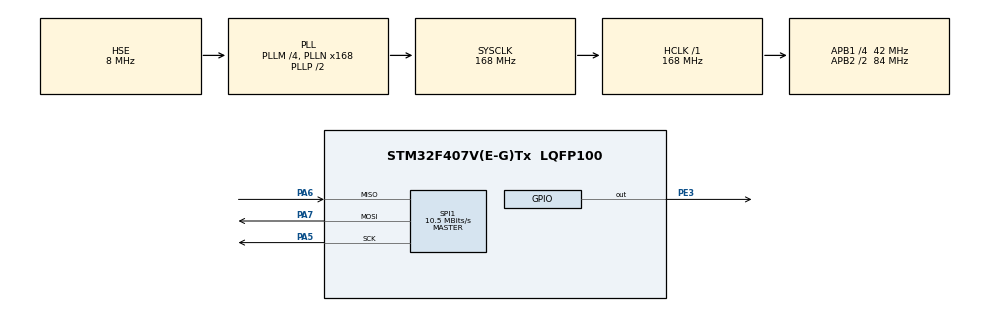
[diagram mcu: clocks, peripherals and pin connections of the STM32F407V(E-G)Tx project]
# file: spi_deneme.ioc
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Mcu.Family=STM32F4
RCC.PLLSourceVirtual=RCC_PLLSOURCE_HSE
PA6.Mode=Full_Duplex_Master
PH0-OSC_IN.Signal=RCC_OSC_IN
RCC.CortexFreq_Value=168000000
PA7.Mode=Full_Duplex_Master
SPI1.VirtualType=VM_MASTER
RCC.APB1CLKDivider=RCC_HCLK_DIV4
RCC.SYSCLKSource=RCC_SYSCLKSOURCE_PLLCLK
ProjectManager.StackSize=0x400
ProjectManager.TargetToolchain=STM32CubeIDE
SPI1.Direction=SPI_DIRECTION_2LINES
RCC.HCLKFreq_Value=168000000
RCC.APB2TimFreq_Value=168000000
SPI1.CalculateBaudRate=10.5 MBits/s
RCC.LSE_VALUE=32768
RCC.AHBFreq_Value=168000000
PH0-OSC_IN.Mode=HSE-External-Oscillator
PE3.PinState=GPIO_PIN_SET
PA5.Signal=SPI1_SCK
RCC.HSE_VALUE=8000000
board=custom
RCC.VCOOutputFreq_Value=336000000
RCC.APB2Freq_Value=84000000
SPI1.Mode=SPI_MODE_MASTER
PH1-OSC_OUT.Signal=RCC_OSC_OUT
Mcu.Name=STM32F407V(E-G)Tx
PH1-OSC_OUT.Mode=HSE-External-Oscillator
RCC.48MHZClocksFreq_Value=84000000
RCC.SYSCLKFreq_VALUE=168000000
Mcu.Package=LQFP100
PA6.Signal=SPI1_MISO
ProjectManager.HeapSize=0x200
RCC.HSI_VALUE=16000000
NVIC.PriorityGroup=NVIC_PRIORITYGROUP_4
RCC.APB2CLKDivider=RCC_HCLK_DIV2
RCC.PLLM=4
RCC.PLLN=168
RCC.APB1TimFreq_Value=84000000
PE3.Signal=GPIO_Output
RCC.APB1Freq_Value=42000000
SPI1.BaudRatePrescaler=SPI_BAUDRATEPRESCALER_8
PA7.Signal=SPI1_MOSI
PA5.Mode=Full_Duplex_Master

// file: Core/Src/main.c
/* USER CODE BEGIN Header */
/**
  ******************************************************************************
  * @file           : main.c
  * @brief          : Main program body
  ******************************************************************************
  * @attention
  *
  * <h2><center>&copy; Copyright (c) 2021 STMicroelectronics.
  * All rights reserved.</center></h2>
  *
  * This software component is licensed by ST under BSD 3-Clause license,
  * the "License"; You may not use this file except in compliance with the
  * License. You may obtain a copy of the License at:
  *                        opensource.org/licenses/BSD-3-Clause
  *
  ******************************************************************************
  */
/* USER CODE END Header */
#include "main.h"

SPI_HandleTypeDef hspi1;

void SystemClock_Config(void);
static void MX_GPIO_Init(void);
static void MX_SPI1_Init(void);

int main(void)
{

  /* MCU Configuration--------------------------------------------------------*/

  /* Reset of all peripherals, Initializes the Flash interface and the Systick. */
  HAL_Init();

  /* Configure the system clock */
  SystemClock_Config();

  /* Initialize all configured peripherals */
  MX_GPIO_Init();
  MX_SPI1_Init();

  uint8_t who_am_i = 0x0f | 0x80;
  uint8_t d = 0;
  HAL_GPIO_WritePin(GPIOE, GPIO_PIN_3, GPIO_PIN_RESET);
  HAL_SPI_Transmit(&hspi1, &who_am_i, 1, 50);
  HAL_SPI_Receive(&hspi1, &d, 1, 50);
  HAL_GPIO_WritePin(GPIOE, GPIO_PIN_3, GPIO_PIN_SET);

  uint8_t tx_buf[2] = {0x20,0x67};
  HAL_GPIO_WritePin(GPIOE, GPIO_PIN_3, GPIO_PIN_RESET);
  HAL_SPI_Transmit(&hspi1, tx_buf, 2, 50);
  HAL_GPIO_WritePin(GPIOE, GPIO_PIN_3, GPIO_PIN_SET);

  tx_buf[0] = 0x24; tx_buf[1] = 0x48;
  HAL_GPIO_WritePin(GPIOE, GPIO_PIN_3, GPIO_PIN_RESET);
  HAL_SPI_Transmit(&hspi1, tx_buf, 2, 50);
  HAL_GPIO_WritePin(GPIOE, GPIO_PIN_3, GPIO_PIN_SET);
  /* Infinite loop */
  /* USER CODE BEGIN WHILE */
  uint8_t add;
  uint8_t x, y, z;
  while (1)
  {
	  add = 0x29 | 0x80;
	  HAL_GPIO_WritePin(GPIOE, GPIO_PIN_3, GPIO_PIN_RESET);
	  HAL_SPI_Transmit(&hspi1, &add, 1, 50);
	  HAL_SPI_Receive(&hspi1, &x, 1, 50);
	  HAL_GPIO_WritePin(GPIOE, GPIO_PIN_3, GPIO_PIN_SET);

	  add = 0x2B | 0x80;
	  HAL_GPIO_WritePin(GPIOE, GPIO_PIN_3, GPIO_PIN_RESET);
	  HAL_SPI_Transmit(&hspi1, &add, 1, 50);
	  HAL_SPI_Receive(&hspi1, &y, 1, 50);
	  HAL_GPIO_WritePin(GPIOE, GPIO_PIN_3, GPIO_PIN_SET);

	  add = 0x2D | 0x80;
	  HAL_GPIO_WritePin(GPIOE, GPIO_PIN_3, GPIO_PIN_RESET);
	  HAL_SPI_Transmit(&hspi1, &add, 1, 50);
	  HAL_SPI_Receive(&hspi1, &z, 1, 50);
	  HAL_GPIO_WritePin(GPIOE, GPIO_PIN_3, GPIO_PIN_SET);

	  if((int8_t)x < -20)
		  HAL_GPIO_WritePin(GPIOD, GPIO_PIN_12, GPIO_PIN_SET);
	  else
		  HAL_GPIO_WritePin(GPIOD, GPIO_PIN_12, GPIO_PIN_RESET);
	  if((int8_t)x > 20)
		  HAL_GPIO_WritePin(GPIOD, GPIO_PIN_14, GPIO_PIN_SET);
	  else
		  HAL_GPIO_WritePin(GPIOD, GPIO_PIN_14, GPIO_PIN_RESET);
	  if((int8_t)y < -20)
		  HAL_GPIO_WritePin(GPIOD, GPIO_PIN_15, GPIO_PIN_SET);
	  else
		  HAL_GPIO_WritePin(GPIOD, GPIO_PIN_15, GPIO_PIN_RESET);
	  if((int8_t)y > 20)
		  HAL_GPIO_WritePin(GPIOD, GPIO_PIN_13, GPIO_PIN_SET);
	  else
		  HAL_GPIO_WritePin(GPIOD, GPIO_PIN_13, GPIO_PIN_RESET);

  }
  /* USER CODE END 3 */
}

void SystemClock_Config(void)
{
  RCC_OscInitTypeDef RCC_OscInitStruct = {0};
  RCC_ClkInitTypeDef RCC_ClkInitStruct = {0};

  /** Configure the main internal regulator output voltage
  */
  __HAL_RCC_PWR_CLK_ENABLE();
  __HAL_PWR_VOLTAGESCALING_CONFIG(PWR_REGULATOR_VOLTAGE_SCALE1);
  /** Initializes the RCC Oscillators according to the specified parameters
  * in the RCC_OscInitTypeDef structure.
  */
  RCC_OscInitStruct.OscillatorType = RCC_OSCILLATORTYPE_HSE;
  RCC_OscInitStruct.HSEState = RCC_HSE_ON;
  RCC_OscInitStruct.PLL.PLLState = RCC_PLL_ON;
  RCC_OscInitStruct.PLL.PLLSource = RCC_PLLSOURCE_HSE;
  RCC_OscInitStruct.PLL.PLLM = 4;
  RCC_OscInitStruct.PLL.PLLN = 168;
  RCC_OscInitStruct.PLL.PLLP = RCC_PLLP_DIV2;
  RCC_OscInitStruct.PLL.PLLQ = 4;
  if (HAL_RCC_OscConfig(&RCC_OscInitStruct) != HAL_OK)
  {
    Error_Handler();
  }
  /** Initializes the CPU, AHB and APB buses clocks
  */
  RCC_ClkInitStruct.ClockType = RCC_CLOCKTYPE_HCLK|RCC_CLOCKTYPE_SYSCLK
                              |RCC_CLOCKTYPE_PCLK1|RCC_CLOCKTYPE_PCLK2;
  RCC_ClkInitStruct.SYSCLKSource = RCC_SYSCLKSOURCE_PLLCLK;
  RCC_ClkInitStruct.AHBCLKDivider = RCC_SYSCLK_DIV1;
  RCC_ClkInitStruct.APB1CLKDivider = RCC_HCLK_DIV4;
  RCC_ClkInitStruct.APB2CLKDivider = RCC_HCLK_DIV2;

  if (HAL_RCC_ClockConfig(&RCC_ClkInitStruct, FLASH_LATENCY_5) != HAL_OK)
  {
    Error_Handler();
  }
}

static void MX_SPI1_Init(void)
{

  /* SPI1 parameter configuration*/
  hspi1.Instance = SPI1;
  hspi1.Init.Mode = SPI_MODE_MASTER;
  hspi1.Init.Direction = SPI_DIRECTION_2LINES;
  hspi1.Init.DataSize = SPI_DATASIZE_8BIT;
  hspi1.Init.CLKPolarity = SPI_POLARITY_LOW;
  hspi1.Init.CLKPhase = SPI_PHASE_1EDGE;
  hspi1.Init.NSS = SPI_NSS_SOFT;
  hspi1.Init.BaudRatePrescaler = SPI_BAUDRATEPRESCALER_4;
  hspi1.Init.FirstBit = SPI_FIRSTBIT_MSB;
  hspi1.Init.TIMode = SPI_TIMODE_DISABLE;
  hspi1.Init.CRCCalculation = SPI_CRCCALCULATION_DISABLE;
  hspi1.Init.CRCPolynomial = 10;
  if (HAL_SPI_Init(&hspi1) != HAL_OK)
  {
    Error_Handler();
  }

}

static void MX_GPIO_Init(void)
{
  GPIO_InitTypeDef GPIO_InitStruct = {0};

  /* GPIO Ports Clock Enable */
  __HAL_RCC_GPIOE_CLK_ENABLE();
  __HAL_RCC_GPIOH_CLK_ENABLE();
  __HAL_RCC_GPIOA_CLK_ENABLE();
  __HAL_RCC_GPIOD_CLK_ENABLE();

  /*Configure GPIO pin Output Level */
  HAL_GPIO_WritePin(GPIOE, GPIO_PIN_3, GPIO_PIN_SET);

  /*Configure GPIO pin : PE3 */
  GPIO_InitStruct.Pin = GPIO_PIN_3;
  GPIO_InitStruct.Mode = GPIO_MODE_OUTPUT_PP;
  GPIO_InitStruct.Pull = GPIO_PULLUP;
  GPIO_InitStruct.Speed = GPIO_SPEED_FREQ_VERY_HIGH;
  HAL_GPIO_Init(GPIOE, &GPIO_InitStruct);

  GPIO_InitStruct.Pin = GPIO_PIN_12 | GPIO_PIN_13 | GPIO_PIN_14 | GPIO_PIN_15;
  GPIO_InitStruct.Mode = GPIO_MODE_OUTPUT_PP;
  GPIO_InitStruct.Pull = GPIO_NOPULL;
  GPIO_InitStruct.Speed = GPIO_SPEED_FREQ_VERY_HIGH;

  HAL_GPIO_Init(GPIOD, &GPIO_InitStruct);

  HAL_GPIO_WritePin(GPIOD, GPIO_PIN_12 | GPIO_PIN_13 | GPIO_PIN_14 | GPIO_PIN_15, GPIO_PIN_RESET);
}

void Error_Handler(void)
{
  __disable_irq();
  while (1)
  {
  }
}

/************************ (C) COPYRIGHT STMicroelectronics *****END OF FILE****/
